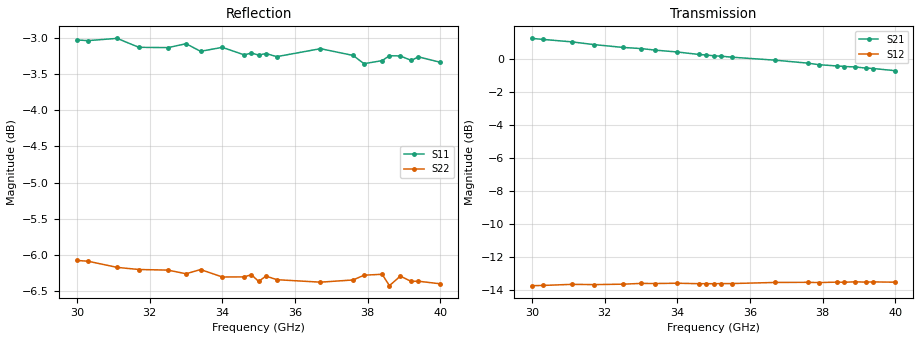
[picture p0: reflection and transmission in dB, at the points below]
!Created with skrf (http://scikit-rf.org).
# Hz S RI R 50.0
!freq ReS11 ImS11 ReS21 ImS21 ReS12 ImS12 ReS22 ImS22
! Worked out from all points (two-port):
!   101 points, 30 GHz to 40 GHz, reference 50 ohm
!   highest |S21| = 1.25 dB at 30 GHz (marker M1); lowest = -0.7 dB at 40 GHz (marker M2)
!   |S21| within 3 dB of the highest: start of sweep to end of sweep
!   lowest |S11| = -3.4 dB at 37.9 GHz (marker M3), VSWR 5.24, Z = 13.3 - j30.7 ohm
!   |S11| at or under -10 dB: nowhere
!   |S22| runs from -6.4 to -6.1 dB; largest |S21 - S12| = 1.1
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3e10  -0.1573 -0.6876  0.0572 1.153  0.1947 0.0643  0.1292 -0.4799
3.03e10  -0.1726 -0.6831  0.0696 1.144  0.1955 0.063  0.1298 -0.4791
3.11e10  -0.177 -0.6846  0.0891 1.123  0.1976 0.0616  0.1171 -0.4774
3.17e10  -0.1923 -0.6701  0.1085 1.1  0.198 0.059  0.1133 -0.4766
3.25e10  -0.2115 -0.6639  0.1297 1.076  0.1994 0.0564  0.1109 -0.4767
3.3e10  -0.2111 -0.6686  0.1385 1.066  0.2007 0.0558  0.1037 -0.4754
3.34e10  -0.2138 -0.6589  0.1474 1.053  0.2009 0.0545  0.0992 -0.4797
3.4e10  -0.2253 -0.6597  0.1618 1.037  0.2019 0.0524  0.0944 -0.4748
3.46e10  -0.2388 -0.6461  0.1783 1.016  0.2019 0.0497  0.0859 -0.4765
3.48e10  -0.2458 -0.6456  0.1807 1.012  0.202 0.0496  0.0933 -0.4768
3.5e10  -0.2447 -0.6437  0.1859 1.005  0.2021 0.0487  0.0839 -0.4733
3.52e10  -0.2495 -0.6436  0.1877 1.002  0.2023 0.0488  0.0911 -0.4762
3.55e10  -0.2484 -0.6404  0.1939 0.9935  0.2025 0.048  0.0814 -0.4751
3.67e10  -0.2697 -0.6412  0.2203 0.9663  0.2048 0.0453  0.0734 -0.4745
3.76e10  -0.2729 -0.6318  0.2331 0.9423  0.2054 0.0433  0.0636 -0.4776
3.79e10  -0.2792 -0.6192  0.2388 0.9302  0.2053 0.042  0.062 -0.4815
3.84e10  -0.2921 -0.6169  0.2495 0.9187  0.2063 0.0404  0.063 -0.4821
3.86e10  -0.2956 -0.6211  0.2529 0.9139  0.2063 0.0394  0.0598 -0.4737
3.89e10  -0.2985 -0.6195  0.2577 0.9097  0.207 0.0391  0.0595 -0.4811
3.92e10  -0.2995 -0.6136  0.2634 0.8999  0.2068 0.0377  0.0494 -0.4782
3.94e10  -0.3017 -0.6168  0.264 0.897  0.2071 0.038  0.0559 -0.4776
4e10  -0.3058 -0.6082  0.2724 0.8799  0.207 0.0359  0.0478 -0.4765
